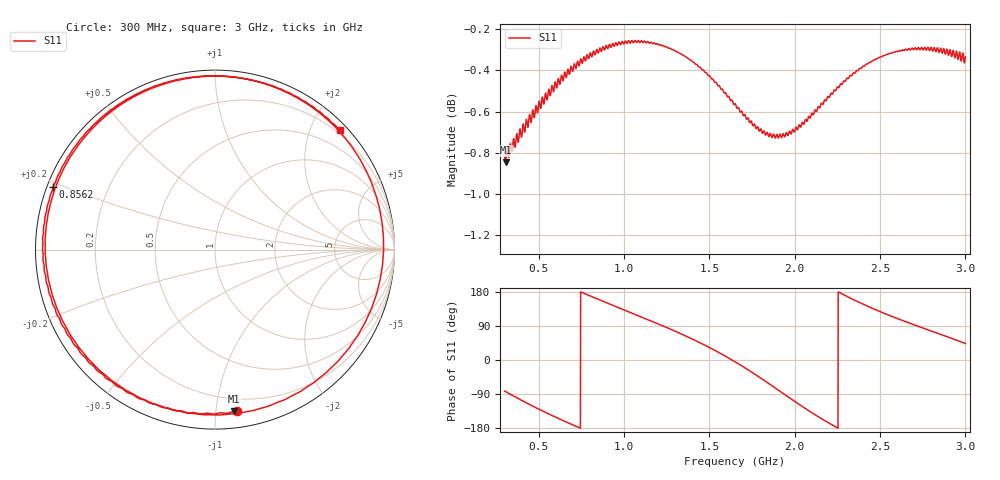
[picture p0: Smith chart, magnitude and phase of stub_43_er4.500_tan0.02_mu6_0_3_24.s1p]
! Chirptenna · simulación 3D de un stub abierto
# HZ S RI R 50
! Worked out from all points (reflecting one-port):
!   2001 points, 300 MHz to 3 GHz, reference 50 ohm
!   lowest |S11| = -0.8 dB at 305.4 MHz (marker M1), VSWR 20.55, Z = 5.49 - j55.9 ohm
!   phase of S11 starts at -82 deg and turns -594 deg over the sweep
!   S11 on the Smith chart (normalised r, x): 300 MHz: 0.11, -1.14; 856.2 MHz: 0.02, +0.19; 3 GHz: 0.14, +2.49
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3e8  0.1243 -0.9014
3.054e8  0.1051 -0.9011
3.7965e8  -0.1863 -0.8983
4.539e8  -0.4524 -0.81
5.511e8  -0.7261 -0.5971
6.375e8  -0.8872 -0.3433
7.3875e8  -0.9579 -0.02
8.562e8  -0.9017 0.3489
9.75e8  -0.7073 0.6631
1.1505e9  -0.2447 0.9384
1.23285e9  0.0169 0.9682
1.3125e9  0.2764 0.9245
1.41105e9  0.5789 0.7648
1.50825e9  0.8149 0.4903
1.58385e9  0.9206 0.2066
1.65e9  0.9345 -0.0738
1.74855e9  0.7849 -0.4944
1.84575e9  0.4404 -0.8085
1.92e9  0.0883 -0.9158
1.9875e9  -0.2453 -0.8908
2.07525e9  -0.6187 -0.6928
2.1549e9  -0.8446 -0.4066
2.2386e9  -0.942 -0.0642
2.325e9  -0.9131 0.2705
2.4924e9  -0.6065 0.7466
2.6625e9  -0.1506 0.9544
2.82585e9  0.295 0.9189
3e9  0.696 0.6646
